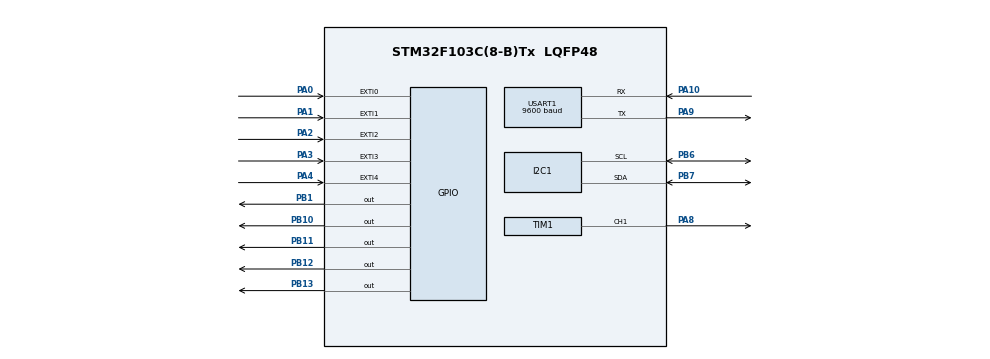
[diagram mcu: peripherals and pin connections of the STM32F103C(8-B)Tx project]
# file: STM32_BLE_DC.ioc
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Mcu.Family=STM32F1
Mcu.Name=STM32F103C(8-B)Tx
Mcu.Package=LQFP48
NVIC.EXTI0_IRQn=true\:0\:0\:false\:false\:true\:true\:true\:true
NVIC.EXTI1_IRQn=true\:0\:0\:false\:false\:true\:true\:true\:true
NVIC.EXTI2_IRQn=true\:0\:0\:false\:false\:true\:true\:true\:true
NVIC.EXTI3_IRQn=true\:0\:0\:false\:false\:true\:true\:true\:true
NVIC.EXTI4_IRQn=true\:0\:0\:false\:false\:true\:true\:true\:true
NVIC.PriorityGroup=NVIC_PRIORITYGROUP_4
PA0-WKUP.GPIO_ModeDefaultEXTI=GPIO_MODE_IT_FALLING
PA0-WKUP.GPIO_PuPd=GPIO_PULLUP
PA0-WKUP.Signal=GPXTI0
PA1.GPIO_ModeDefaultEXTI=GPIO_MODE_IT_FALLING
PA1.GPIO_PuPd=GPIO_PULLUP
PA1.Signal=GPXTI1
PA10.Mode=Asynchronous
PA10.Signal=USART1_RX
PA13.Mode=Serial_Wire
PA13.Signal=SYS_JTMS-SWDIO
PA14.Mode=Serial_Wire
PA14.Signal=SYS_JTCK-SWCLK
PA2.GPIO_ModeDefaultEXTI=GPIO_MODE_IT_FALLING
PA2.GPIO_PuPd=GPIO_PULLUP
PA2.Signal=GPXTI2
PA3.GPIO_ModeDefaultEXTI=GPIO_MODE_IT_FALLING
PA3.GPIO_PuPd=GPIO_PULLUP
PA3.Signal=GPXTI3
PA4.GPIO_ModeDefaultEXTI=GPIO_MODE_IT_FALLING
PA4.GPIO_PuPd=GPIO_PULLUP
PA4.Signal=GPXTI4
PA8.Signal=S_TIM1_CH1
PA9.Mode=Asynchronous
PA9.Signal=USART1_TX
PB1.Signal=GPIO_Output
PB10.Signal=GPIO_Output
PB11.Signal=GPIO_Output
PB12.Signal=GPIO_Output
PB13.Signal=GPIO_Output
PB6.Mode=I2C
PB6.Signal=I2C1_SCL
PB7.Mode=I2C
PB7.Signal=I2C1_SDA
PD0-OSC_IN.Mode=HSE-External-Oscillator
PD0-OSC_IN.Signal=RCC_OSC_IN
PD1-OSC_OUT.Mode=HSE-External-Oscillator
PD1-OSC_OUT.Signal=RCC_OSC_OUT
ProjectManager.HeapSize=0x200
ProjectManager.StackSize=0x400
ProjectManager.TargetToolchain=MDK-ARM V5.32
RCC.AHBFreq_Value=72000000
RCC.APB1CLKDivider=RCC_HCLK_DIV2
RCC.APB1Freq_Value=36000000
RCC.APB1TimFreq_Value=72000000
RCC.APB2Freq_Value=72000000
RCC.APB2TimFreq_Value=72000000
RCC.EnbaleCSS=true
RCC.HCLKFreq_Value=72000000
RCC.PLLMUL=RCC_PLL_MUL9
RCC.PLLSourceVirtual=RCC_PLLSOURCE_HSE
RCC.SYSCLKFreq_VALUE=72000000
RCC.SYSCLKSource=RCC_SYSCLKSOURCE_PLLCLK
RCC.USBFreq_Value=72000000
SH.S_TIM1_CH1.0=TIM1_CH1,PWM Generation1 CH1
TIM1.Channel-PWM\ Generation1\ CH1=TIM_CHANNEL_1
TIM1.Period=999
TIM1.Prescaler=71
TIM4.Period=65534
TIM4.Prescaler=71
USART1.BaudRate=9600
USART1.VirtualMode=VM_ASYNC
VP_TIM1_VS_ClockSourceINT.Mode=Internal
VP_TIM4_VS_ClockSourceINT.Mode=Internal
board=custom

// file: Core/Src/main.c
#include "main.h"
#include "stdio.h"
#include "string.h"
#include "DHT.h"
#include "lcd_i2c.h"

I2C_HandleTypeDef hi2c1;
TIM_HandleTypeDef htim1;
TIM_HandleTypeDef htim4;
UART_HandleTypeDef huart1;

void SystemClock_Config(void);
static void MX_GPIO_Init(void);
static void MX_I2C1_Init(void);
static void MX_TIM1_Init(void);
static void MX_TIM4_Init(void);
static void MX_USART1_UART_Init(void);

#define DHT_GPIO_Port GPIOB
#define DHT_Pin GPIO_PIN_11
#define LED_FAN_PORT   GPIOB
#define LED_FAN_PIN    GPIO_PIN_10
#define LED_AUTO_PORT  GPIOB
#define LED_AUTO_PIN   GPIO_PIN_1

int fan_level = 0;
int fan_power = 0;
int auto_mode = 0;
int fan_level_old = 0;
int fan_power_old = 0;
int auto_mode_old = 0;

char M[100];
char buffer_rx[1];
char buffer_tx[20];

float temperature = 0.0;

void Fan_SetLevel (int level)
{
	fan_level = level;
	switch(level)
	{
		case 0: __HAL_TIM_SET_COMPARE(&htim1, TIM_CHANNEL_1, 0); break;
		case 1: __HAL_TIM_SET_COMPARE(&htim1, TIM_CHANNEL_1, 333); break;
		case 2: __HAL_TIM_SET_COMPARE(&htim1, TIM_CHANNEL_1, 666); break;
		case 3: __HAL_TIM_SET_COMPARE(&htim1, TIM_CHANNEL_1, 999); break;
	}
}

void HM10_Process(char cmd)
{
	if(cmd == '0')
	{
		fan_power ^= 1;
		if(fan_power == 0)
		{
			Fan_SetLevel(0);
			auto_mode = 0;
		}
	}
	else if(cmd == '1' && fan_power) auto_mode ^= 1;
	else if(cmd == '2' && fan_power && auto_mode == 0) Fan_SetLevel(1);
	else if(cmd == '3' && fan_power && auto_mode == 0) Fan_SetLevel(2);
	else if(cmd == '4' && fan_power && auto_mode == 0) Fan_SetLevel(3);
}

void LCD_Update()
{
	Lcd_xoa_manhinh();
	Lcd_Ghi_Lenh(0x80);
	sprintf(M,"Nhiet do: %.1f'C",temperature);
	Lcd_Ghi_Chuoi(M);
	Lcd_Ghi_Lenh(0xC0);
	if(auto_mode) sprintf(M,"Auto:On    Lv: %d",fan_level);
	else sprintf(M,"Auto:Off   Lv: %d",fan_level);
	Lcd_Ghi_Chuoi(M);

	int len = sprintf(M,
											"#0:%.1f'C\r\n"
											"#1:%s Lv:%d\r\n",
											temperature,
											auto_mode ? "Auto" : "Man ",
											fan_level
										);
	HAL_UART_Transmit(&huart1, (uint8_t*)M, len, 100);

	if(fan_power != fan_power_old)
	{
    int lenn;

    if(fan_power)
        lenn = sprintf(M, "@Power On\r\n");
    else
        lenn = sprintf(M, "@Power Off\r\n");

    HAL_UART_Transmit(&huart1, (uint8_t*)M, lenn, 100);

    fan_power_old = fan_power;
	}
}

void LED_Update(void)
{
	if(fan_power)
		HAL_GPIO_WritePin(LED_FAN_PORT, LED_FAN_PIN, 1);
	else
		HAL_GPIO_WritePin(LED_FAN_PORT, LED_FAN_PIN, 0);

	if(auto_mode)
		HAL_GPIO_WritePin(LED_AUTO_PORT, LED_AUTO_PIN, 1);
	else
		HAL_GPIO_WritePin(LED_AUTO_PORT, LED_AUTO_PIN, 0);
}

void EXTI0_IRQHandler(void)
{
    HAL_GPIO_EXTI_IRQHandler(GPIO_PIN_0);
}

void EXTI1_IRQHandler(void)
{
    HAL_GPIO_EXTI_IRQHandler(GPIO_PIN_1);
}

void EXTI2_IRQHandler(void)
{
    HAL_GPIO_EXTI_IRQHandler(GPIO_PIN_2);
}

void EXTI3_IRQHandler(void)
{
    HAL_GPIO_EXTI_IRQHandler(GPIO_PIN_3);
}

void EXTI4_IRQHandler(void)
{
    HAL_GPIO_EXTI_IRQHandler(GPIO_PIN_4);
}

void HAL_GPIO_EXTI_Callback(uint16_t GPIO_Pin)
{
    static uint32_t last_tick = 0;
    if (HAL_GetTick() - last_tick < 200) return;
    last_tick = HAL_GetTick();

    switch (GPIO_Pin)
    {
        case GPIO_PIN_0:
            fan_power ^= 1;
            if (fan_power == 0)
            {
                Fan_SetLevel(0);
                auto_mode = 0;
            }
            break;

        case GPIO_PIN_1:
						if(fan_power)
							auto_mode ^= 1;
            break;

        case GPIO_PIN_2:   // Level 1
            if (auto_mode == 0 && fan_power)
                Fan_SetLevel(1);
            break;

        case GPIO_PIN_3:   // Level 2
            if (auto_mode == 0 && fan_power)
                Fan_SetLevel(2);
            break;

        case GPIO_PIN_4:   // Level 3
            if (auto_mode == 0 && fan_power)
                Fan_SetLevel(3);
            break;
    }
}

int main(void)
{
  HAL_Init();

  SystemClock_Config();

  MX_GPIO_Init();
  MX_I2C1_Init();
  MX_TIM1_Init();
	MX_TIM4_Init();
  MX_USART1_UART_Init();

	HAL_TIM_Base_Start(&htim1);
	HAL_TIM_Base_Start(&htim4);
	HAL_TIM_PWM_Start(&htim1, TIM_CHANNEL_1);

	lcd_init();

	DHT11_InitTypeDef dht;
	DHT11_StatusTypeDef err;
	HAL_DHT11_Init(&dht, GPIOB, GPIO_PIN_11, &htim4);

	Fan_SetLevel(0);

	HAL_GPIO_WritePin(GPIOB,GPIO_PIN_12,1);
	HAL_GPIO_WritePin(GPIOB,GPIO_PIN_13,0);

	Lcd_xoa_manhinh();
	Lcd_Ghi_Lenh(0x84);
	sprintf(M,"Wait.....");
	Lcd_Ghi_Chuoi(M);
	HAL_Delay(1000);
	LCD_Update();
	LED_Update();

  while (1)
	{
		/*        ===== Task 1: DHT(1 giây) ===== */
    static uint32_t t_dht = 0;
    if (HAL_GetTick() - t_dht >= 1000)
    {
			t_dht = HAL_GetTick();

			HAL_DHT11_ReadData(&dht);
			temperature = dht.Temperature;

			if (auto_mode && fan_power)
			{
				if (temperature < 30)
						Fan_SetLevel(1);
				else if (temperature < 36)
						Fan_SetLevel(2);
				else
						Fan_SetLevel(3);
			}
    }

    /* ===== Task 2: LCD + LED (400 ms) ===== */
    static uint32_t t_ui = 0;
    if (HAL_GetTick() - t_ui >= 400)
    {
			t_ui = HAL_GetTick();

			LCD_Update();
			LED_Update();
    }

		/* ===== Task 3: BLE ===== */
    if(HAL_UART_Receive(&huart1, buffer_rx, 1, 100) == HAL_OK)
    {
			char cmd = buffer_rx[0];
			HM10_Process(cmd);
    }

	}

}

void SystemClock_Config(void)
{
  RCC_OscInitTypeDef RCC_OscInitStruct = {0};
  RCC_ClkInitTypeDef RCC_ClkInitStruct = {0};

  /* 1. Kh?i t?o HSI + PLL */
  RCC_OscInitStruct.OscillatorType = RCC_OSCILLATORTYPE_HSI;
  RCC_OscInitStruct.HSIState = RCC_HSI_ON;
  RCC_OscInitStruct.HSICalibrationValue = RCC_HSICALIBRATION_DEFAULT;

  RCC_OscInitStruct.PLL.PLLState = RCC_PLL_ON;
  RCC_OscInitStruct.PLL.PLLSource = RCC_PLLSOURCE_HSI_DIV2; // 8MHz / 2 = 4MHz
  RCC_OscInitStruct.PLL.PLLMUL = RCC_PLL_MUL16;             // 4MHz × 16 = 64MHz

  if (HAL_RCC_OscConfig(&RCC_OscInitStruct) != HAL_OK)
  {
    Error_Handler();
  }

  /* 2. Ch?n clock h? th?ng */
  RCC_ClkInitStruct.ClockType = RCC_CLOCKTYPE_HCLK
                              |RCC_CLOCKTYPE_SYSCLK
                              |RCC_CLOCKTYPE_PCLK1
                              |RCC_CLOCKTYPE_PCLK2;

  RCC_ClkInitStruct.SYSCLKSource = RCC_SYSCLKSOURCE_PLLCLK;
  RCC_ClkInitStruct.AHBCLKDivider = RCC_SYSCLK_DIV1;   // HCLK = 64 MHz
  RCC_ClkInitStruct.APB1CLKDivider = RCC_HCLK_DIV2;    // APB1 = 32 MHz (=36MHz)
  RCC_ClkInitStruct.APB2CLKDivider = RCC_HCLK_DIV1;    // APB2 = 64 MHz

  if (HAL_RCC_ClockConfig(&RCC_ClkInitStruct, FLASH_LATENCY_2) != HAL_OK)
  {
    Error_Handler();
  }

  /* 3. KHÔNG b?t CSS khi dùng HSI */
  // HAL_RCC_EnableCSS();  // <-- b?
}

static void MX_I2C1_Init(void)
{

  hi2c1.Instance = I2C1;
  hi2c1.Init.ClockSpeed = 100000;
  hi2c1.Init.DutyCycle = I2C_DUTYCYCLE_2;
  hi2c1.Init.OwnAddress1 = 0;
  hi2c1.Init.AddressingMode = I2C_ADDRESSINGMODE_7BIT;
  hi2c1.Init.DualAddressMode = I2C_DUALADDRESS_DISABLE;
  hi2c1.Init.OwnAddress2 = 0;
  hi2c1.Init.GeneralCallMode = I2C_GENERALCALL_DISABLE;
  hi2c1.Init.NoStretchMode = I2C_NOSTRETCH_DISABLE;
  if (HAL_I2C_Init(&hi2c1) != HAL_OK)
  {
    Error_Handler();
  }

}

static void MX_TIM1_Init(void)
{

  TIM_ClockConfigTypeDef sClockSourceConfig = {0};
  TIM_MasterConfigTypeDef sMasterConfig = {0};
  TIM_OC_InitTypeDef sConfigOC = {0};
  TIM_BreakDeadTimeConfigTypeDef sBreakDeadTimeConfig = {0};

  htim1.Instance = TIM1;
  htim1.Init.Prescaler = 71;
  htim1.Init.CounterMode = TIM_COUNTERMODE_UP;
  htim1.Init.Period = 999;
  htim1.Init.ClockDivision = TIM_CLOCKDIVISION_DIV1;
  htim1.Init.RepetitionCounter = 0;
  htim1.Init.AutoReloadPreload = TIM_AUTORELOAD_PRELOAD_DISABLE;
  if (HAL_TIM_Base_Init(&htim1) != HAL_OK)
  {
    Error_Handler();
  }
  sClockSourceConfig.ClockSource = TIM_CLOCKSOURCE_INTERNAL;
  if (HAL_TIM_ConfigClockSource(&htim1, &sClockSourceConfig) != HAL_OK)
  {
    Error_Handler();
  }
  if (HAL_TIM_PWM_Init(&htim1) != HAL_OK)
  {
    Error_Handler();
  }
  sMasterConfig.MasterOutputTrigger = TIM_TRGO_RESET;
  sMasterConfig.MasterSlaveMode = TIM_MASTERSLAVEMODE_DISABLE;
  if (HAL_TIMEx_MasterConfigSynchronization(&htim1, &sMasterConfig) != HAL_OK)
  {
    Error_Handler();
  }
  sConfigOC.OCMode = TIM_OCMODE_PWM1;
  sConfigOC.Pulse = 0;
  sConfigOC.OCPolarity = TIM_OCPOLARITY_HIGH;
  sConfigOC.OCNPolarity = TIM_OCNPOLARITY_HIGH;
  sConfigOC.OCFastMode = TIM_OCFAST_DISABLE;
  sConfigOC.OCIdleState = TIM_OCIDLESTATE_RESET;
  sConfigOC.OCNIdleState = TIM_OCNIDLESTATE_RESET;
  if (HAL_TIM_PWM_ConfigChannel(&htim1, &sConfigOC, TIM_CHANNEL_1) != HAL_OK)
  {
    Error_Handler();
  }
  sBreakDeadTimeConfig.OffStateRunMode = TIM_OSSR_DISABLE;
  sBreakDeadTimeConfig.OffStateIDLEMode = TIM_OSSI_DISABLE;
  sBreakDeadTimeConfig.LockLevel = TIM_LOCKLEVEL_OFF;
  sBreakDeadTimeConfig.DeadTime = 0;
  sBreakDeadTimeConfig.BreakState = TIM_BREAK_DISABLE;
  sBreakDeadTimeConfig.BreakPolarity = TIM_BREAKPOLARITY_HIGH;
  sBreakDeadTimeConfig.AutomaticOutput = TIM_AUTOMATICOUTPUT_DISABLE;
  if (HAL_TIMEx_ConfigBreakDeadTime(&htim1, &sBreakDeadTimeConfig) != HAL_OK)
  {
    Error_Handler();
  }
  HAL_TIM_MspPostInit(&htim1);

}

static void MX_TIM4_Init(void)
{

  TIM_ClockConfigTypeDef sClockSourceConfig = {0};
  TIM_MasterConfigTypeDef sMasterConfig = {0};

  htim4.Instance = TIM4;
  htim4.Init.Prescaler = 71;
  htim4.Init.CounterMode = TIM_COUNTERMODE_UP;
  htim4.Init.Period = 65534;
  htim4.Init.ClockDivision = TIM_CLOCKDIVISION_DIV1;
  htim4.Init.AutoReloadPreload = TIM_AUTORELOAD_PRELOAD_DISABLE;
  if (HAL_TIM_Base_Init(&htim4) != HAL_OK)
  {
    Error_Handler();
  }
  sClockSourceConfig.ClockSource = TIM_CLOCKSOURCE_INTERNAL;
  if (HAL_TIM_ConfigClockSource(&htim4, &sClockSourceConfig) != HAL_OK)
  {
    Error_Handler();
  }
  sMasterConfig.MasterOutputTrigger = TIM_TRGO_RESET;
  sMasterConfig.MasterSlaveMode = TIM_MASTERSLAVEMODE_DISABLE;
  if (HAL_TIMEx_MasterConfigSynchronization(&htim4, &sMasterConfig) != HAL_OK)
  {
    Error_Handler();
  }

}

static void MX_USART1_UART_Init(void)
{

  huart1.Instance = USART1;
  huart1.Init.BaudRate = 9600;
  huart1.Init.WordLength = UART_WORDLENGTH_8B;
  huart1.Init.StopBits = UART_STOPBITS_1;
  huart1.Init.Parity = UART_PARITY_NONE;
  huart1.Init.Mode = UART_MODE_TX_RX;
  huart1.Init.HwFlowCtl = UART_HWCONTROL_NONE;
  huart1.Init.OverSampling = UART_OVERSAMPLING_16;
  if (HAL_UART_Init(&huart1) != HAL_OK)
  {
    Error_Handler();
  }

}

static void MX_GPIO_Init(void)
{
  GPIO_InitTypeDef GPIO_InitStruct = {0};

  /* GPIO Ports Clock Enable */
  __HAL_RCC_GPIOD_CLK_ENABLE();
  __HAL_RCC_GPIOA_CLK_ENABLE();
  __HAL_RCC_GPIOB_CLK_ENABLE();

  /*Configure GPIO pin Output Level */
  HAL_GPIO_WritePin(GPIOB, GPIO_PIN_1|GPIO_PIN_10|GPIO_PIN_11|GPIO_PIN_12
                          |GPIO_PIN_13, GPIO_PIN_RESET);

  /*Configure GPIO pins : PA0 PA1 PA2 PA3
                           PA4 */
  GPIO_InitStruct.Pin = GPIO_PIN_0|GPIO_PIN_1|GPIO_PIN_2|GPIO_PIN_3
                          |GPIO_PIN_4;
  GPIO_InitStruct.Mode = GPIO_MODE_IT_FALLING;
  GPIO_InitStruct.Pull = GPIO_PULLUP;
  HAL_GPIO_Init(GPIOA, &GPIO_InitStruct);

  /*Configure GPIO pins : PB1 PB10 PB11 PB12
                           PB13 */
  GPIO_InitStruct.Pin = GPIO_PIN_1|GPIO_PIN_10|GPIO_PIN_11|GPIO_PIN_12
                          |GPIO_PIN_13;
  GPIO_InitStruct.Mode = GPIO_MODE_OUTPUT_PP;
  GPIO_InitStruct.Pull = GPIO_NOPULL;
  GPIO_InitStruct.Speed = GPIO_SPEED_FREQ_LOW;
  HAL_GPIO_Init(GPIOB, &GPIO_InitStruct);

  /* EXTI interrupt init*/
  HAL_NVIC_SetPriority(EXTI0_IRQn, 0, 0);
  HAL_NVIC_EnableIRQ(EXTI0_IRQn);

  HAL_NVIC_SetPriority(EXTI1_IRQn, 0, 0);
  HAL_NVIC_EnableIRQ(EXTI1_IRQn);

  HAL_NVIC_SetPriority(EXTI2_IRQn, 0, 0);
  HAL_NVIC_EnableIRQ(EXTI2_IRQn);

  HAL_NVIC_SetPriority(EXTI3_IRQn, 0, 0);
  HAL_NVIC_EnableIRQ(EXTI3_IRQn);

  HAL_NVIC_SetPriority(EXTI4_IRQn, 0, 0);
  HAL_NVIC_EnableIRQ(EXTI4_IRQn);

}

void Error_Handler(void)
{
  __disable_irq();
  while (1)
  {
  }
}
